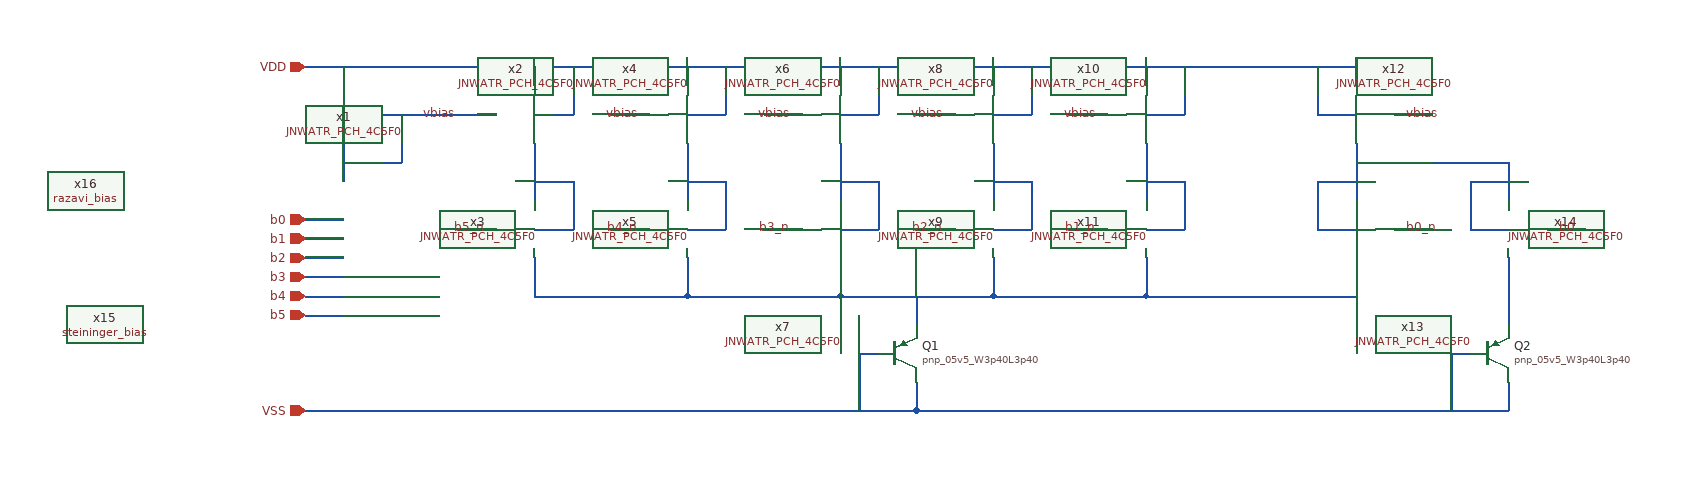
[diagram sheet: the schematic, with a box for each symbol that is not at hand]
v {xschem version=3.4.6 file_version=1.2}
G {}
K {}
V {}
S {}
E {}
N 520 -550 640 -550 {lab=vbias}
N 480 -600 480 -580 {lab=VDD}
N 680 -600 680 -580 {lab=VDD}
N 480 -520 480 -480 {lab=vbias}
N 680 -520 680 -460 {lab=#net1}
N 680 -360 840 -360 {lab=#net2}
N 1080 -360 1080 -330 {lab=#net2}
N 680 -400 680 -360 {lab=#net2}
N 600 -430 640 -430 {lab=b5_n}
N 760 -550 800 -550 {lab=vbias}
N 840 -600 840 -580 {lab=VDD}
N 840 -520 840 -460 {lab=#net3}
N 840 -400 840 -360 {lab=#net2}
N 760 -430 800 -430 {lab=b4_n}
N 680 -430 720 -430 {lab=#net1}
N 720 -480 720 -430 {lab=#net1}
N 680 -480 720 -480 {lab=#net1}
N 680 -550 720 -550 {lab=VDD}
N 720 -600 720 -550 {lab=VDD}
N 840 -550 880 -550 {lab=VDD}
N 880 -600 880 -550 {lab=VDD}
N 840 -430 880 -430 {lab=#net3}
N 880 -480 880 -430 {lab=#net3}
N 840 -480 880 -480 {lab=#net3}
N 840 -360 1000 -360 {lab=#net2}
N 920 -550 960 -550 {lab=vbias}
N 1000 -600 1000 -580 {lab=VDD}
N 1000 -520 1000 -460 {lab=#net4}
N 1000 -400 1000 -360 {lab=#net2}
N 920 -430 960 -430 {lab=b3_n}
N 1000 -550 1040 -550 {lab=VDD}
N 1040 -600 1040 -550 {lab=VDD}
N 1000 -430 1040 -430 {lab=#net4}
N 1040 -480 1040 -430 {lab=#net4}
N 1000 -480 1040 -480 {lab=#net4}
N 1000 -360 1160 -360 {lab=#net2}
N 1080 -550 1120 -550 {lab=vbias}
N 1160 -600 1160 -580 {lab=VDD}
N 1160 -520 1160 -460 {lab=#net5}
N 1160 -400 1160 -360 {lab=#net2}
N 1080 -430 1120 -430 {lab=b2_n}
N 1160 -550 1200 -550 {lab=VDD}
N 1200 -600 1200 -550 {lab=VDD}
N 1160 -430 1200 -430 {lab=#net5}
N 1200 -480 1200 -430 {lab=#net5}
N 1160 -480 1200 -480 {lab=#net5}
N 1160 -360 1320 -360 {lab=#net2}
N 1240 -550 1280 -550 {lab=vbias}
N 1320 -600 1320 -580 {lab=VDD}
N 1320 -520 1320 -460 {lab=#net6}
N 1320 -400 1320 -360 {lab=#net2}
N 1240 -430 1280 -430 {lab=b1_n}
N 1320 -550 1360 -550 {lab=VDD}
N 1360 -600 1360 -550 {lab=VDD}
N 1320 -430 1360 -430 {lab=#net6}
N 1360 -480 1360 -430 {lab=#net6}
N 1320 -480 1360 -480 {lab=#net6}
N 440 -600 1540 -600 {lab=VDD}
N 1580 -550 1620 -550 {lab=vbias}
N 1540 -600 1540 -580 {lab=VDD}
N 1540 -520 1540 -460 {lab=#net7}
N 1540 -400 1540 -360 {lab=#net2}
N 1580 -430 1620 -430 {lab=b0_n}
N 1500 -550 1540 -550 {lab=VDD}
N 1500 -600 1500 -550 {lab=VDD}
N 1500 -430 1540 -430 {lab=#net7}
N 1500 -480 1500 -430 {lab=#net7}
N 1500 -480 1540 -480 {lab=#net7}
N 480 -500 540 -500 {lab=vbias}
N 540 -550 540 -500 {lab=vbias}
N 1540 -500 1700 -500 {lab=#net7}
N 1700 -500 1700 -460 {lab=#net7}
N 1700 -400 1700 -330 {lab=#net8}
N 1740 -430 1780 -430 {lab=b0}
N 1660 -430 1700 -430 {lab=#net7}
N 1660 -480 1660 -430 {lab=#net7}
N 1660 -480 1700 -480 {lab=#net7}
N 1320 -360 1540 -360 {lab=#net2}
N 1080 -270 1080 -240 {lab=VSS}
N 1080 -240 1700 -240 {lab=VSS}
N 1700 -270 1700 -240 {lab=VSS}
N 1640 -300 1660 -300 {lab=VSS}
N 1640 -300 1640 -240 {lab=VSS}
N 1020 -300 1040 -300 {lab=VSS}
N 1020 -300 1020 -240 {lab=VSS}
N 440 -240 1080 -240 {lab=VSS}
N 440 -440 480 -440 {lab=b0}
N 440 -420 480 -420 {lab=b1}
N 440 -400 480 -400 {lab=b2}
N 440 -380 480 -380 {lab=b3}
N 440 -360 480 -360 {lab=b4}
N 440 -340 480 -340 {lab=b5}
C {JNW_ATR_SKY130A/JNWATR_PCH_4C5F0.sym} 520 -550 0 1 {name=x1 }
C {JNW_ATR_SKY130A/JNWATR_PCH_4C5F0.sym} 640 -550 0 0 {name=x2 }
C {JNW_ATR_SKY130A/JNWATR_PCH_4C5F0.sym} 640 -430 0 0 {name=x3 }
C {JNW_ATR_SKY130A/JNWATR_PCH_4C5F0.sym} 800 -550 0 0 {name=x4 }
C {JNW_ATR_SKY130A/JNWATR_PCH_4C5F0.sym} 800 -430 0 0 {name=x5 }
C {JNW_ATR_SKY130A/JNWATR_PCH_4C5F0.sym} 960 -550 0 0 {name=x6 }
C {JNW_ATR_SKY130A/JNWATR_PCH_4C5F0.sym} 960 -430 0 0 {name=x7 }
C {JNW_ATR_SKY130A/JNWATR_PCH_4C5F0.sym} 1120 -550 0 0 {name=x8 }
C {JNW_ATR_SKY130A/JNWATR_PCH_4C5F0.sym} 1120 -430 0 0 {name=x9 }
C {JNW_ATR_SKY130A/JNWATR_PCH_4C5F0.sym} 1280 -550 0 0 {name=x10 }
C {JNW_ATR_SKY130A/JNWATR_PCH_4C5F0.sym} 1280 -430 0 0 {name=x11 }
C {JNW_ATR_SKY130A/JNWATR_PCH_4C5F0.sym} 1580 -550 0 1 {name=x12 }
C {JNW_ATR_SKY130A/JNWATR_PCH_4C5F0.sym} 1580 -430 0 1 {name=x13 }
C {devices/lab_wire.sym} 630 -430 0 0 {name=p1 sig_type=std_logic lab=b5_n}
C {devices/lab_wire.sym} 790 -430 0 0 {name=p2 sig_type=std_logic lab=b4_n
}
C {devices/lab_wire.sym} 950 -430 0 0 {name=p3 sig_type=std_logic lab=b3_n
}
C {devices/lab_wire.sym} 1110 -430 0 0 {name=p4 sig_type=std_logic lab=b2_n
}
C {devices/lab_wire.sym} 1270 -430 0 0 {name=p5 sig_type=std_logic lab=b1_n
}
C {devices/lab_wire.sym} 1590 -430 0 1 {name=p6 sig_type=std_logic lab=b0_n
}
C {devices/lab_wire.sym} 560 -550 0 1 {name=p7 sig_type=std_logic lab=vbias}
C {JNW_ATR_SKY130A/JNWATR_PCH_4C5F0.sym} 1740 -430 0 1 {name=x14 }
C {devices/lab_wire.sym} 1750 -430 0 1 {name=p13 sig_type=std_logic lab=b0
}
C {devices/ipin.sym} 440 -600 0 0 {name=p14 lab=VDD}
C {sky130_fd_pr/pnp_05v5.sym} 1060 -300 0 0 {name=Q1
model=pnp_05v5_W3p40L3p40
m=1
spiceprefix=X
}
C {sky130_fd_pr/pnp_05v5.sym} 1680 -300 0 0 {name=Q2
model=pnp_05v5_W3p40L3p40
m=1
spiceprefix=X
}
C {LELO_TORD_SKY130A/steininger_bias.sym} 230 -330 0 0 {name=x15}
C {LELO_TORD_SKY130A/razavi_bias.sym} 210 -470 0 0 {name=x16}
C {devices/ipin.sym} 440 -240 0 0 {name=p15 lab=VSS}
C {devices/ipin.sym} 440 -440 0 0 {name=p16 lab=b0}
C {devices/ipin.sym} 440 -420 0 0 {name=p17 lab=b1}
C {devices/ipin.sym} 440 -400 0 0 {name=p18 lab=b2}
C {devices/ipin.sym} 440 -380 0 0 {name=p19 lab=b3}
C {devices/ipin.sym} 440 -360 0 0 {name=p20 lab=b4}
C {devices/ipin.sym} 440 -340 0 0 {name=p21 lab=b5}
C {devices/lab_wire.sym} 790 -550 0 0 {name=p8 sig_type=std_logic lab=vbias}
C {devices/lab_wire.sym} 950 -550 0 0 {name=p9 sig_type=std_logic lab=vbias}
C {devices/lab_wire.sym} 1110 -550 0 0 {name=p10 sig_type=std_logic lab=vbias}
C {devices/lab_wire.sym} 1270 -550 0 0 {name=p11 sig_type=std_logic lab=vbias}
C {devices/lab_wire.sym} 1590 -550 0 1 {name=p22 sig_type=std_logic lab=vbias}
